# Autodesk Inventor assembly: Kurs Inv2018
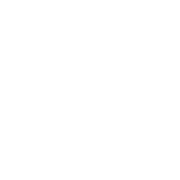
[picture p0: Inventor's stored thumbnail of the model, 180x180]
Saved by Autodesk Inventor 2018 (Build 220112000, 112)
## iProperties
Created: 2010-03
Part Number: Kurs Inv2018
Document SubType Name: Assembly
Designer: Johan Wedeen
Manufacturer: Standard
Standards Organization: Custom
Author: Johan Wedeen
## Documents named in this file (1)
- C:\Users\Public\Documents\Autodesk\Inventor 2018\Templates\InventorKurs\Kurs Inv2018.iam
